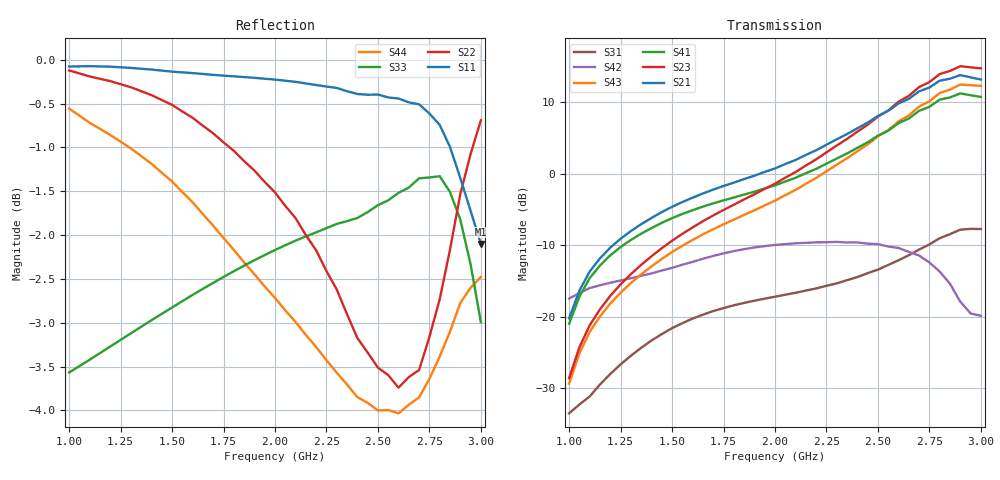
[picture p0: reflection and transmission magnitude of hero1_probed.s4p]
# GHz S RI R 50
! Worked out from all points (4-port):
!   41 points, 1 GHz to 3 GHz, reference 50 ohm
!   strongest paths, dB at 1 GHz, 1.5 GHz, 2 GHz, 2.5 GHz, 3 GHz:
!     S21: -20.2, -4.6, 0.7, 8.1, 13.1
!     S23: -28.6, -9.4, -1.4, 8.0, 14.7
!     S41: -21.0, -6.2, -1.7, 5.3, 10.7
!     S43: -29.4, -11.0, -3.8, 5.2, 12.3
!     S42: -17.5, -13.2, -10.0, -9.8, -19.9
!     S31: -33.5, -21.6, -17.2, -13.4, -7.7
!   lowest |S11| = -2.1 dB at 3 GHz (marker M1), VSWR 8.31, Z = 22.9 + j81.5 ohm
!   |S11| at or under -10 dB: nowhere
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1  -0.6607 0.7389  0.00128 0.000883  -0.0125 0.0171  0.00111 0.000888
   -0.0171 0.096  -0.6338 0.7555  -0.0364 -0.00771  0.0983 0.091
   -0.0125 0.0171  -0.000353 0.000478  0.3945 -0.5331  -0.000353 0.000414
   -0.0217 0.0865  0.0983 0.091  -0.0328 -0.00937  -0.7911 0.504
2  -0.00869 0.9744  -0.000624 0.00105  0.000168 0.138  -0.000706 0.000604
   1.021 0.3728  0.468 0.6979  -0.3283 0.784  0.2876 -0.1342
   0.000168 0.138  -0.000797 -0.000526  -0.0877 -0.774  -0.000447 -0.000573
   0.6448 0.5176  0.2876 -0.1342  -0.4278 0.485  -0.3598 0.6368
2.5  0.2389 0.9251  0.00178 0.00386  0.0637 0.2037  -0.00036 0.00307
     1.552 -1.997  0.617 0.2545  1.897 1.625  0.0911 -0.3086
     0.0637 0.2037  -0.00389 0.00158  -0.3567 -0.7453  -0.00302 -0.0005
     1.722 -0.6488  0.0911 -0.3086  0.5593 1.73  -0.2824 0.5642
2.7  0.3594 0.8721  0.00321 0.00358  0.1175 0.2703  0.000291 0.0035
     -0.2632 -3.747  0.6365 0.1939  4.021 -0.0909  -0.0293 -0.2659
     0.1175 0.2703  -0.00399 0.00325  -0.5092 -0.6879  -0.00376 0.000133
     1.502 -2.299  -0.0293 -0.2659  2.383 1.723  -0.3016 0.5666
2.8  0.4165 0.8182  0.00276 0.0036  0.1756 0.307  -0.000149 0.00333
     -2.334 -3.798  0.7072 0.1816  4.343 -2.394  -0.0593 -0.1982
     0.1756 0.307  -0.00414 0.00287  -0.5936 -0.6199  -0.0037 -0.000341
     0.4815 -3.248  -0.0593 -0.1982  3.584 0.7062  -0.3152 0.5995
2.9  0.4342 0.738  0.00143 0.00482  0.269 0.3036  -0.00166 0.00336
     -4.441 -2.014  0.8291 0.124  2.563 -5.01  -0.0388 -0.1214
     0.269 0.3036  -0.00564 0.00138  -0.6358 -0.5032  -0.00378 -0.0021
     -1.407 -3.348  -0.0388 -0.1214  3.936 -1.44  -0.3096 0.6574
3  0.3899 0.6815  0.00236 0.00673  0.3427 0.2255  -0.00239 0.00483
   -4.422 1.048  0.9232 -0.0327  -1.003 -5.341  0.0217 -0.0992
   0.3427 0.2255  -0.00818 0.00244  -0.5866 -0.3973  -0.00564 -0.00312
   -2.903 -1.831  0.0217 -0.0992  2.35 -3.365  -0.2598 0.7055
